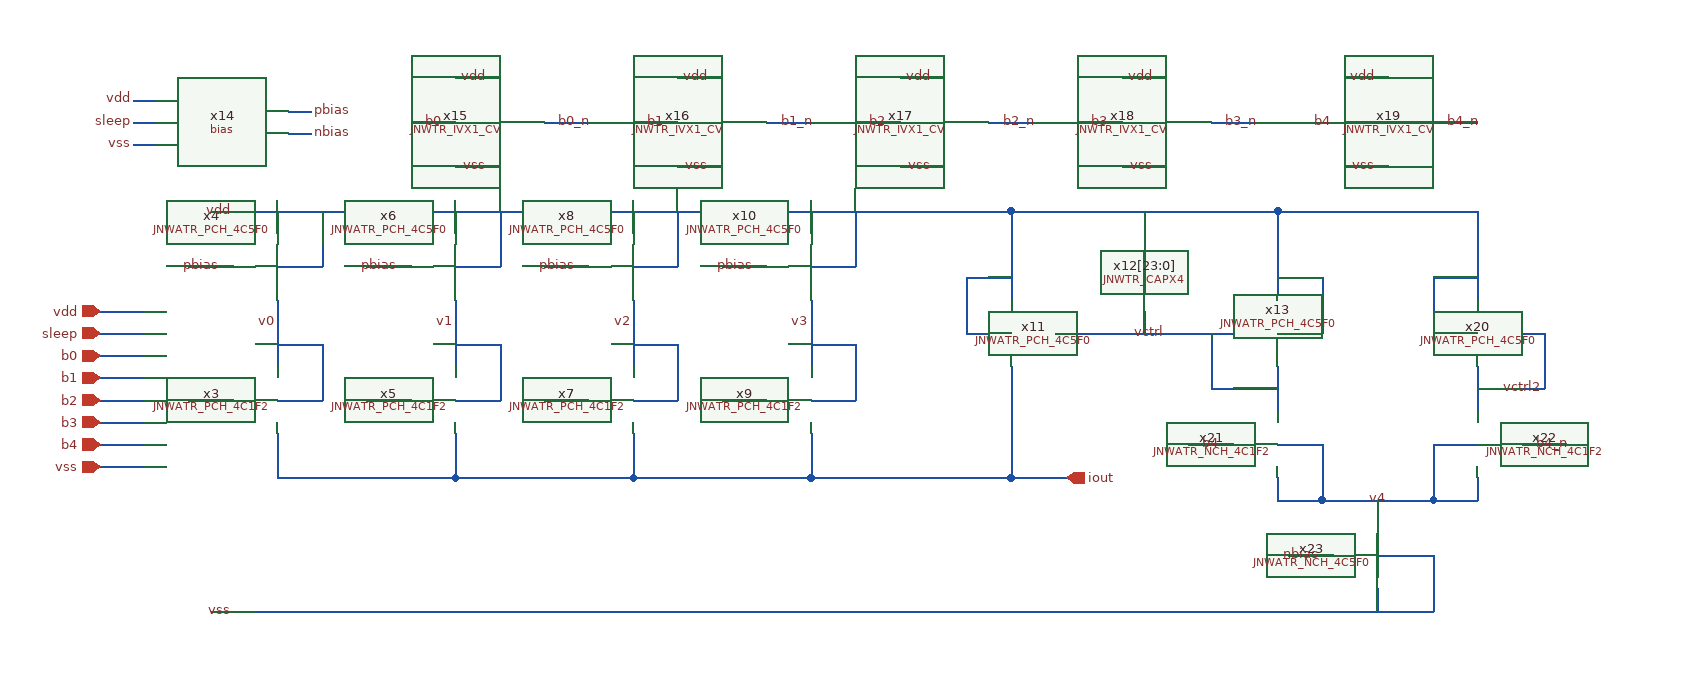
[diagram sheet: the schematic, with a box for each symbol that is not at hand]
v {xschem version=3.4.6 file_version=1.2}
G {}
K {}
V {}
S {}
E {}
N 520 350 560 350 {lab=pbias}
N 600 300 600 320 {lab=vdd}
N 600 380 600 440 {lab=v0}
N 600 500 600 540 {lab=iout}
N 520 470 560 470 {lab=b0_n}
N 600 350 640 350 {lab=vdd}
N 640 300 640 350 {lab=vdd}
N 600 470 640 470 {lab=v0}
N 640 420 640 470 {lab=v0}
N 600 420 640 420 {lab=v0}
N 600 540 760 540 {lab=iout}
N 680 350 720 350 {lab=pbias}
N 760 300 760 320 {lab=vdd}
N 760 380 760 440 {lab=v1}
N 760 500 760 540 {lab=iout}
N 680 470 720 470 {lab=b1_n}
N 760 350 800 350 {lab=vdd}
N 800 300 800 350 {lab=vdd}
N 760 470 800 470 {lab=v1}
N 800 420 800 470 {lab=v1}
N 760 420 800 420 {lab=v1}
N 760 540 920 540 {lab=iout}
N 840 350 880 350 {lab=pbias}
N 920 300 920 320 {lab=vdd}
N 920 380 920 440 {lab=v2}
N 920 500 920 540 {lab=iout}
N 840 470 880 470 {lab=b2_n}
N 920 350 960 350 {lab=vdd}
N 960 300 960 350 {lab=vdd}
N 920 470 960 470 {lab=v2}
N 960 420 960 470 {lab=v2}
N 920 420 960 420 {lab=v2}
N 920 540 1080 540 {lab=iout}
N 1000 350 1040 350 {lab=pbias}
N 1080 300 1080 320 {lab=vdd}
N 1080 380 1080 440 {lab=v3}
N 1080 500 1080 540 {lab=iout}
N 1000 470 1040 470 {lab=b3_n}
N 1080 350 1120 350 {lab=vdd}
N 1120 300 1120 350 {lab=vdd}
N 1080 470 1120 470 {lab=v3}
N 1120 420 1120 470 {lab=v3}
N 1080 420 1120 420 {lab=v3}
N 540 300 1260 300 {lab=vdd}
N 720 220 760 220 {lab=b0}
N 440 450 480 450 {lab=b1}
N 440 470 480 470 {lab=b2}
N 440 490 480 490 {lab=b3}
N 440 510 480 510 {lab=b4}
N 760 180 800 180 {lab=vdd}
N 760 260 800 260 {lab=vss}
N 840 220 880 220 {lab=b0_n}
N 920 220 960 220 {lab=b1}
N 960 180 1000 180 {lab=vdd}
N 960 260 1000 260 {lab=vss}
N 1040 220 1080 220 {lab=b1_n}
N 1120 220 1160 220 {lab=b2}
N 1160 180 1200 180 {lab=vdd}
N 1160 260 1200 260 {lab=vss}
N 1240 220 1280 220 {lab=b2_n}
N 1320 220 1360 220 {lab=b3}
N 1360 180 1400 180 {lab=vdd}
N 1360 260 1400 260 {lab=vss}
N 1440 220 1480 220 {lab=b3_n}
N 1520 220 1560 220 {lab=b4}
N 1560 180 1600 180 {lab=vdd}
N 1560 260 1600 260 {lab=vss}
N 1640 220 1680 220 {lab=b4_n}
N 440 430 480 430 {lab=b0}
N 470 220 490 220 {lab=sleep}
N 610 230 630 230 {lab=nbias}
N 610 210 630 210 {lab=pbias}
N 470 240 490 240 {lab=vss}
N 470 200 490 200 {lab=vdd}
N 1300 410 1460 410 {lab=vctrl}
N 1260 300 1260 380 {lab=vdd}
N 1080 540 1260 540 {lab=iout}
N 1380 390 1380 410 {lab=vctrl}
N 1380 300 1380 320 {lab=vdd}
N 1260 300 1500 300 {lab=vdd}
N 1500 300 1500 380 {lab=vdd}
N 1500 410 1540 410 {lab=vdd}
N 1540 360 1540 410 {lab=vdd}
N 1500 360 1540 360 {lab=vdd}
N 1440 410 1440 460 {lab=vctrl}
N 1440 460 1500 460 {lab=vctrl}
N 1500 440 1500 480 {lab=vctrl}
N 1720 410 1740 410 {lab=vctrl2}
N 1680 300 1680 380 {lab=vdd}
N 1640 410 1680 410 {lab=vdd}
N 1640 360 1640 410 {lab=vdd}
N 1740 410 1740 460 {lab=vctrl2}
N 1680 460 1740 460 {lab=vctrl2}
N 1680 440 1680 480 {lab=vctrl2}
N 1500 300 1680 300 {lab=vdd}
N 1640 360 1680 360 {lab=vdd}
N 1260 440 1260 540 {lab=iout}
N 1640 510 1680 510 {lab=v4}
N 1640 510 1640 560 {lab=v4}
N 1640 560 1680 560 {lab=v4}
N 1500 510 1540 510 {lab=v4}
N 1540 510 1540 560 {lab=v4}
N 1500 560 1540 560 {lab=v4}
N 1500 540 1500 560 {lab=v4}
N 1680 540 1680 560 {lab=v4}
N 1420 510 1460 510 {lab=b4}
N 1720 510 1760 510 {lab=b4_n}
N 1540 560 1640 560 {lab=v4}
N 1590 560 1590 580 {lab=v4}
N 1640 610 1640 660 {lab=vss}
N 1220 410 1260 410 {lab=vdd}
N 1220 360 1220 410 {lab=vdd}
N 1220 360 1260 360 {lab=vdd}
N 1590 640 1590 660 {lab=vss}
N 1590 610 1640 610 {lab=vss}
N 540 660 1640 660 {lab=vss}
N 1510 610 1550 610 {lab=nbias}
N 1260 540 1310 540 {lab=iout}
N 440 410 480 410 {lab=sleep}
N 440 390 480 390 {lab=vdd}
N 440 530 480 530 {lab=vss}
C {JNW_ATR_SKY130A/JNWATR_PCH_4C5F0.sym} 560 350 0 0 {name=x4 }
C {JNW_ATR_SKY130A/JNWATR_PCH_4C5F0.sym} 720 350 0 0 {name=x6 }
C {JNW_ATR_SKY130A/JNWATR_PCH_4C5F0.sym} 880 350 0 0 {name=x8 }
C {JNW_ATR_SKY130A/JNWATR_PCH_4C5F0.sym} 1040 350 0 0 {name=x10 }
C {devices/lab_wire.sym} 1030 470 0 0 {name=p3 sig_type=std_logic lab=b3_n
}
C {devices/lab_wire.sym} 870 470 0 0 {name=p4 sig_type=std_logic lab=b2_n
}
C {devices/lab_wire.sym} 710 470 0 0 {name=p5 sig_type=std_logic lab=b1_n
}
C {devices/lab_wire.sym} 550 470 0 0 {name=p6 sig_type=std_logic lab=b0_n
}
C {devices/ipin.sym} 440 390 0 0 {name=p14 lab=vdd}
C {devices/ipin.sym} 440 530 0 0 {name=p15 lab=vss}
C {devices/ipin.sym} 440 450 0 0 {name=p17 lab=b1}
C {devices/ipin.sym} 440 470 0 0 {name=p18 lab=b2}
C {devices/ipin.sym} 440 490 0 0 {name=p19 lab=b3}
C {devices/ipin.sym} 440 510 0 0 {name=p20 lab=b4}
C {JNW_TR_SKY130A/JNWTR_IVX1_CV.sym} 760 220 0 0 {name=x15 }
C {devices/lab_wire.sym} 790 260 2 1 {name=p23 sig_type=std_logic lab=vss}
C {devices/lab_wire.sym} 790 180 0 0 {name=p24 sig_type=std_logic lab=vdd}
C {JNW_TR_SKY130A/JNWTR_IVX1_CV.sym} 960 220 0 0 {name=x16 }
C {devices/lab_wire.sym} 990 260 2 1 {name=p26 sig_type=std_logic lab=vss}
C {devices/lab_wire.sym} 990 180 0 0 {name=p27 sig_type=std_logic lab=vdd}
C {JNW_TR_SKY130A/JNWTR_IVX1_CV.sym} 1160 220 0 0 {name=x17 }
C {devices/lab_wire.sym} 1190 260 2 1 {name=p30 sig_type=std_logic lab=vss}
C {devices/lab_wire.sym} 1190 180 0 0 {name=p31 sig_type=std_logic lab=vdd}
C {JNW_TR_SKY130A/JNWTR_IVX1_CV.sym} 1360 220 0 0 {name=x18 }
C {devices/lab_wire.sym} 1390 260 2 1 {name=p34 sig_type=std_logic lab=vss}
C {devices/lab_wire.sym} 1390 180 0 0 {name=p35 sig_type=std_logic lab=vdd}
C {JNW_TR_SKY130A/JNWTR_IVX1_CV.sym} 1560 220 0 0 {name=x19 }
C {devices/lab_wire.sym} 1590 260 2 1 {name=p38 sig_type=std_logic lab=vss}
C {devices/lab_wire.sym} 1590 180 0 0 {name=p39 sig_type=std_logic lab=vdd}
C {devices/lab_wire.sym} 750 220 0 0 {name=p16 sig_type=std_logic lab=b0}
C {devices/lab_wire.sym} 1350 220 0 0 {name=p25 sig_type=std_logic lab=b3}
C {devices/lab_wire.sym} 950 220 0 0 {name=p28 sig_type=std_logic lab=b1}
C {devices/lab_wire.sym} 1550 220 0 0 {name=p29 sig_type=std_logic lab=b4}
C {devices/lab_wire.sym} 1150 220 0 0 {name=p32 sig_type=std_logic lab=b2}
C {devices/ipin.sym} 440 430 0 0 {name=p7 lab=b0}
C {devices/lab_wire.sym} 1450 220 0 1 {name=p36 sig_type=std_logic lab=b3_n}
C {devices/lab_wire.sym} 850 220 0 1 {name=p37 sig_type=std_logic lab=b0_n}
C {devices/lab_wire.sym} 1050 220 0 1 {name=p40 sig_type=std_logic lab=b1_n}
C {devices/lab_wire.sym} 1650 220 0 1 {name=p41 sig_type=std_logic lab=b4_n}
C {devices/lab_wire.sym} 1250 220 0 1 {name=p45 sig_type=std_logic lab=b2_n}
C {devices/lab_wire.sym} 710 350 0 0 {name=p9 sig_type=std_logic lab=pbias
}
C {devices/lab_wire.sym} 870 350 0 0 {name=p8 sig_type=std_logic lab=pbias
}
C {devices/lab_wire.sym} 1030 350 0 0 {name=p10 sig_type=std_logic lab=pbias
}
C {devices/lab_wire.sym} 550 350 0 0 {name=p12 sig_type=std_logic lab=pbias
}
C {LELO_TORD_SKY130A/bias.sym} 550 220 0 0 {name=x14}
C {devices/ipin.sym} 440 410 0 0 {name=p33 lab=sleep}
C {devices/lab_wire.sym} 630 210 0 1 {name=p13 sig_type=std_logic lab=pbias
}
C {devices/lab_wire.sym} 630 230 0 1 {name=p21 sig_type=std_logic lab=nbias
}
C {JNW_ATR_SKY130A/JNWATR_PCH_4C5F0.sym} 1300 410 0 1 {name=x11 }
C {JNW_ATR_SKY130A/JNWATR_PCH_4C1F2.sym} 560 470 0 0 {name=x3 }
C {JNW_ATR_SKY130A/JNWATR_PCH_4C1F2.sym} 720 470 0 0 {name=x5 }
C {JNW_ATR_SKY130A/JNWATR_PCH_4C1F2.sym} 880 470 0 0 {name=x7 }
C {JNW_ATR_SKY130A/JNWATR_PCH_4C1F2.sym} 1040 470 0 0 {name=x9 }
C {JNW_TR_SKY130A/JNWTR_CAPX4.sym} 1380 380 0 0 {name=x12[23:0]}
C {JNW_ATR_SKY130A/JNWATR_PCH_4C5F0.sym} 1460 410 0 0 {name=x13 }
C {JNW_ATR_SKY130A/JNWATR_PCH_4C5F0.sym} 1720 410 0 1 {name=x20 }
C {JNW_ATR_SKY130A/JNWATR_NCH_4C1F2.sym} 1460 510 0 0 {name=x21 }
C {JNW_ATR_SKY130A/JNWATR_NCH_4C1F2.sym} 1720 510 0 1 {name=x22 }
C {devices/lab_wire.sym} 1730 510 0 1 {name=p1 sig_type=std_logic lab=b4_n}
C {devices/lab_wire.sym} 1450 510 0 0 {name=p2 sig_type=std_logic lab=b4}
C {JNW_ATR_SKY130A/JNWATR_NCH_4C5F0.sym} 1550 610 0 0 {name=x23 }
C {devices/lab_wire.sym} 1540 610 0 0 {name=p11 sig_type=std_logic lab=nbias
}
C {devices/lab_wire.sym} 1400 410 2 1 {name=p42 sig_type=std_logic lab=vctrl}
C {devices/lab_wire.sym} 1700 460 2 0 {name=p43 sig_type=std_logic lab=vctrl2}
C {devices/lab_wire.sym} 1600 560 0 0 {name=p44 sig_type=std_logic lab=v4}
C {devices/lab_wire.sym} 1080 400 2 1 {name=p46 sig_type=std_logic lab=v3}
C {devices/lab_wire.sym} 920 400 2 1 {name=p47 sig_type=std_logic lab=v2}
C {devices/lab_wire.sym} 760 400 2 1 {name=p48 sig_type=std_logic lab=v1}
C {devices/lab_wire.sym} 600 400 2 1 {name=p49 sig_type=std_logic lab=v0
}
C {devices/lab_wire.sym} 470 240 0 0 {name=p50 sig_type=std_logic lab=vss
}
C {devices/lab_wire.sym} 470 200 0 0 {name=p51 sig_type=std_logic lab=vdd
}
C {devices/opin.sym} 1310 540 0 0 {name=p54 lab=iout}
C {devices/lab_wire.sym} 560 300 0 0 {name=p22 sig_type=std_logic lab=vdd
}
C {devices/lab_wire.sym} 560 660 0 0 {name=p52 sig_type=std_logic lab=vss
}
C {devices/lab_wire.sym} 470 220 0 0 {name=p53 sig_type=std_logic lab=sleep
}
